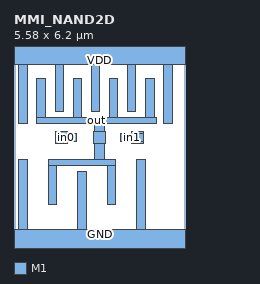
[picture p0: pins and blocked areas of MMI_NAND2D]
MACRO MMI_NAND2D
	CLASS CORE ;
	FOREIGN MMI_NAND2D 0 0 ;
	SIZE 5.58 BY 6.2 ;
	SYMMETRY X Y ;
	SITE CORE1 ;
	PIN out
		DIRECTION output ;
		USE SIGNAL ;
		PORT
			LAYER M1 ;
			RECT 0.75 4.05 1.03 5.325 ;
			LAYER M1 ;
			RECT 1.93 4.05 2.21 5.325 ;
			LAYER M1 ;
			RECT 3.11 4.05 3.39 5.325 ;
			LAYER M1 ;
			RECT 4.29 4.05 4.57 5.325 ;
			LAYER M1 ;
			RECT 0.75 3.855 4.66 4.05 ;
			LAYER M1 ;
			RECT 2.625 3.6 2.955 3.855 ;
			LAYER M1 ;
			RECT 2.6 3.22 2.98 3.6 ;
			LAYER M1 ;
			RECT 2.625 2.7 2.955 3.22 ;
			LAYER M1 ;
			RECT 1.12 2.505 3.32 2.7 ;
			LAYER M1 ;
			RECT 1.12 1.225 1.4 2.505 ;
			LAYER M1 ;
			RECT 3.04 1.225 3.32 2.505 ;
		END
		AntennaDiffArea 4.0656 ;
	END out
	PIN in1
		DIRECTION input ;
		USE SIGNAL ;
		PORT
			LAYER M1 ;
			RECT 3.84 3.55 4.22 3.6 ;
			LAYER M1 ;
			RECT 3.48 3.27 4.22 3.55 ;
			LAYER M1 ;
			RECT 3.84 3.22 4.22 3.27 ;
		END
		AntennaGateArea 1.848 ;
	END in1
	PIN GND
		DIRECTION inout ;
		USE GROUND ;
		PORT
			LAYER M1 ;
			RECT 0.16 0.42 0.44 2.695 ;
			LAYER M1 ;
			RECT 2.08 0.42 2.36 2.285 ;
			LAYER M1 ;
			RECT 4 0.42 4.28 2.695 ;
			LAYER M1 ;
			RECT 0 -0.42 5.58 0.42 ;
		END
	END GND
	PIN VDD
		DIRECTION inout ;
		USE POWER ;
		PORT
			LAYER M1 ;
			RECT 0 5.78 5.58 6.62 ;
			LAYER M1 ;
			RECT 0.16 3.855 0.44 5.78 ;
			LAYER M1 ;
			RECT 1.34 4.265 1.62 5.78 ;
			LAYER M1 ;
			RECT 2.52 4.265 2.8 5.78 ;
			LAYER M1 ;
			RECT 3.7 4.265 3.98 5.78 ;
			LAYER M1 ;
			RECT 4.88 3.855 5.16 5.78 ;
		END
	END VDD
	PIN in0
		DIRECTION input ;
		USE SIGNAL ;
		PORT
			LAYER M1 ;
			RECT 1.36 3.55 1.74 3.6 ;
			LAYER M1 ;
			RECT 1.36 3.27 2.045 3.55 ;
			LAYER M1 ;
			RECT 1.36 3.22 1.74 3.27 ;
		END
		AntennaGateArea 1.848 ;
	END in0
	OBS
	END
END MMI_NAND2D
